VERSION 5.7 ;
  NOWIREEXTENSIONATPIN ON ;
  DIVIDERCHAR "/" ;
  BUSBITCHARS "[]" ;
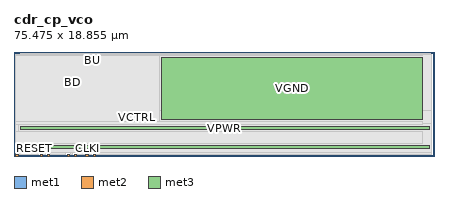
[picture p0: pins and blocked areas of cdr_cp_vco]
MACRO cdr_cp_vco
  CLASS BLOCK ;
  FOREIGN cdr_cp_vco ;
  ORIGIN 0.000 0.000 ;
  SIZE 75.475 BY 18.855 ;
  PIN BU
    ANTENNAGATEAREA 9.721000 ;
    ANTENNADIFFAREA 0.650000 ;
    PORT
      LAYER met1 ;
        RECT 13.965 17.220 14.350 17.530 ;
    END
  END BU
  PIN BD
    ANTENNAGATEAREA 10.682099 ;
    ANTENNADIFFAREA 0.447500 ;
    PORT
      LAYER met1 ;
        RECT 10.375 13.005 10.770 13.320 ;
    END
  END BD
  PIN VCTRL
    ANTENNAGATEAREA 1.241700 ;
    ANTENNADIFFAREA 2.143000 ;
    PORT
      LAYER met2 ;
        RECT 21.960 6.060 22.230 7.910 ;
    END
  END VCTRL
  PIN CLKI
    ANTENNADIFFAREA 0.604500 ;
    PORT
      LAYER met2 ;
        RECT 12.935 0.000 13.305 0.260 ;
    END
  END CLKI
  PIN CLKI_N
    ANTENNADIFFAREA 0.541300 ;
    PORT
      LAYER met2 ;
        RECT 14.240 0.000 14.610 0.260 ;
    END
  END CLKI_N
  PIN CLKQ
    ANTENNADIFFAREA 0.604500 ;
    PORT
      LAYER met2 ;
        RECT 9.525 0.000 9.895 0.260 ;
    END
  END CLKQ
  PIN CLKQ_N
    ANTENNADIFFAREA 0.541300 ;
    PORT
      LAYER met2 ;
        RECT 10.830 0.000 11.200 0.260 ;
    END
  END CLKQ_N
  PIN UP_N
    ANTENNAGATEAREA 0.279000 ;
    ANTENNADIFFAREA 0.585900 ;
    PORT
      LAYER met2 ;
        RECT 4.685 0.000 5.055 0.260 ;
    END
  END UP_N
  PIN DOWN_N
    ANTENNAGATEAREA 0.279000 ;
    ANTENNADIFFAREA 0.585900 ;
    PORT
      LAYER met2 ;
        RECT 5.990 0.000 6.360 0.260 ;
    END
  END DOWN_N
  PIN RESET
    ANTENNAGATEAREA 0.222000 ;
    PORT
      LAYER met2 ;
        RECT 0.355 0.000 0.725 0.260 ;
    END
  END RESET
  PIN VGND
    USE GROUND ;
    PORT
      LAYER met3 ;
        RECT 26.550 6.645 73.400 17.695 ;
    END
    PORT
      LAYER met3 ;
        RECT 3.130 1.430 74.620 1.920 ;
    END
  END VGND
  PIN VPWR
    USE POWER ;
    PORT
      LAYER met3 ;
        RECT 1.200 4.760 74.620 5.250 ;
    END
  END VPWR
  OBS
      LAYER nwell ;
        RECT 1.010 1.675 74.810 18.210 ;
      LAYER li1 ;
        RECT 1.200 1.430 74.795 18.340 ;
      LAYER met1 ;
        RECT 1.200 17.810 74.825 18.245 ;
        RECT 1.200 16.940 13.685 17.810 ;
        RECT 14.630 16.940 74.825 17.810 ;
        RECT 1.200 13.600 74.825 16.940 ;
        RECT 1.200 12.725 10.095 13.600 ;
        RECT 11.050 12.725 74.825 13.600 ;
        RECT 1.200 0.995 74.825 12.725 ;
      LAYER met2 ;
        RECT 0.320 8.190 75.010 18.290 ;
        RECT 0.320 5.780 21.680 8.190 ;
        RECT 22.510 5.780 75.010 8.190 ;
        RECT 0.320 0.540 75.010 5.780 ;
        RECT 1.005 0.260 4.405 0.540 ;
        RECT 5.335 0.260 5.710 0.540 ;
        RECT 6.640 0.260 9.245 0.540 ;
        RECT 10.175 0.260 10.550 0.540 ;
        RECT 11.480 0.260 12.655 0.540 ;
        RECT 13.585 0.260 13.960 0.540 ;
        RECT 14.890 0.260 75.010 0.540 ;
      LAYER met3 ;
        RECT 0.320 18.095 73.350 18.170 ;
        RECT 0.320 6.245 26.150 18.095 ;
        RECT 0.320 5.650 73.350 6.245 ;
        RECT 0.320 4.360 0.800 5.650 ;
        RECT 0.320 2.320 73.350 4.360 ;
        RECT 0.320 1.430 2.730 2.320 ;
  END
END cdr_cp_vco
END LIBRARY

